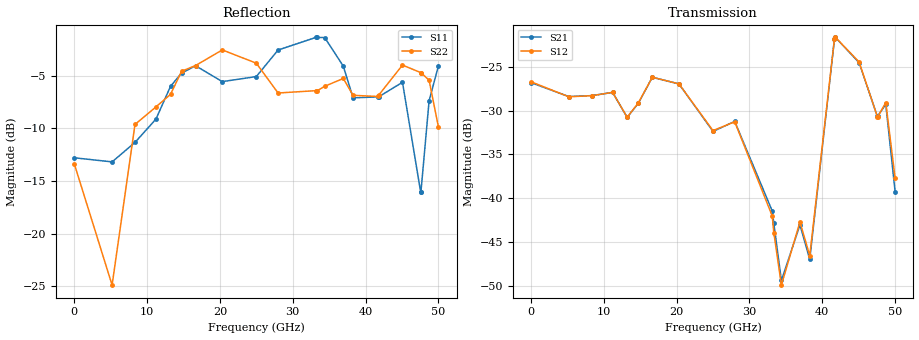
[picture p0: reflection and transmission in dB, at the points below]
!Keysight Technologies,N5245B,MY58422270,A.16.20.02
!Date: Thursday, March 05, 2026 01:35:48
!Correction: S11(C  2-Port  )
!S21(C  2-Port  )
!S12(C  2-Port  )
!S22(C  2-Port  )
!S2P File: Measurements: S11, S21, S12, S22:
# Hz S  dB  R 50
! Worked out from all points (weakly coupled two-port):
!   3201 points, 10 MHz to 50 GHz, reference 50 ohm
!   highest |S21| = -21.62 dB at 41.81 GHz (marker M1); lowest = -49.4 dB at 34.39 GHz (marker M2)
!   lowest |S11| = -16.1 dB at 47.56 GHz (marker M3), VSWR 1.37, Z = 44.7 + j14.1 ohm
!   |S11| at or under -10 dB: start of sweep to 9.791 GHz; 11.44 GHz to 11.86 GHz (420.2 MHz wide, 3.61 % of centre); 46.74 GHz to 48.32 GHz (1.577 GHz wide, 3.32 % of centre)
!   |S22| runs from -24.9 to -2.5 dB; largest |S21 - S12| = 0.0029
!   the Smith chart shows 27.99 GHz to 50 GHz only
!   S11 on the Smith chart (normalised r, x): 27.99 GHz: 0.20, +0.57; 33.14 GHz: 0.68, +2.68; 36.94 GHz: 1.52, -1.90; 47.59 GHz: 0.92, +0.30; 50 GHz: 0.54, -1.08
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1e7  -12.79 -3.9  -26.78 0.7  -26.68 2.0  -13.34 34.1
5.212084e9  -13.18 -129.9  -28.38 163.9  -28.40 163.9  -24.88 -131.0
8.352081e9  -11.33 170.1  -28.27 32.9  -28.28 32.8  -9.63 -151.7
1.122651e10  -9.12 100.5  -27.90 -71.1  -27.90 -71.3  -7.96 92.2
1.322611e10  -6.01 60.9  -30.76 -120.9  -30.74 -121.5  -6.77 -17.7
1.475705e10  -4.74 13.4  -29.14 -148.5  -29.10 -148.6  -4.57 -88.3
1.667854e10  -4.06 -44.5  -26.17 157.9  -26.17 157.8  -4.03 -141.6
2.033406e10  -5.56 -126.8  -26.93 40.0  -26.93 39.9  -2.55 153.6
2.5005e10  -5.08 171.2  -32.36 -66.1  -32.27 -67.7  -3.81 70.7
2.798878e10  -2.56 119.1  -31.22 -132.2  -31.26 -133.0  -6.64 16.5
3.3144e10  -1.37 38.9  -41.48 10.9  -42.06 19.0  -6.42 -126.0
3.334708e10  -1.36 35.5  -42.85 0.5  -43.93 5.9  -6.43 -130.5
3.439375e10  -1.38 17.4  -49.41 -106.3  -49.94 -102.4  -6.00 -153.6
3.694011e10  -4.09 -37.6  -43.05 95.3  -42.71 98.9  -5.26 156.5
3.828359e10  -7.10 -20.5  -47.00 104.8  -46.57 115.1  -6.86 134.1
4.167354e10  -7.01 -56.5  -21.81 -61.1  -21.79 -62.2  -6.97 113.4
4.181414e10  -7.00 -56.7  -21.62 -74.4  -21.61 -75.5  -6.83 112.5
4.506349e10  -5.62 -105.0  -24.51 89.5  -24.43 89.1  -3.99 76.0
4.756299e10  -16.06 102.0  -30.65 -14.1  -30.68 -14.0  -4.70 41.8
4.759423e10  -16.04 96.6  -30.62 -14.3  -30.72 -14.5  -4.70 41.5
4.871901e10  -7.37 -26.1  -29.27 -89.5  -29.06 -89.3  -5.43 19.3
5e10  -4.06 -78.0  -39.27 -129.0  -37.70 -119.5  -9.88 6.7
